VERSION 5.8 ;
BUSBITCHARS "[]" ;
DIVIDERCHAR "/" ;
UNITS
    DATABASE MICRONS 1000 ;
END UNITS

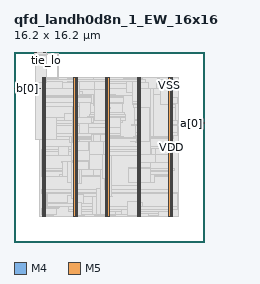
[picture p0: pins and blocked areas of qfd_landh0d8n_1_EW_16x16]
MACRO qfd_landh0d8n_1_EW_16x16
  FOREIGN qfd_landh0d8n_1_EW_16x16 0 0 ;
  CLASS BLOCK ;
  SIZE 16.2 BY 16.2 ;
  PIN a[0]
    DIRECTION INPUT ;
    USE SIGNAL ;
    PORT
      LAYER M4 ;
        RECT  16.116 10.128 16.2 10.152 ;
    END
    PORT
      LAYER M4 ;
        RECT  15.397 10.128 16.14 10.152 ;
    END
  END a[0]
  PIN b[0]
    DIRECTION OUTPUT ;
    USE SIGNAL ;
    PORT
      LAYER M4 ;
        RECT  0 13.104 0.084 13.128 ;
    END
    PORT
      LAYER M4 ;
        RECT  0.06 13.104 2.252 13.128 ;
    END
  END b[0]
  PIN ck
    DIRECTION INPUT ;
    USE SIGNAL ;
    PORT
      LAYER M5 ;
        RECT  1.776 16.116 1.8 16.2 ;
    END
  END ck
  PIN ck_s
    DIRECTION INPUT ;
    USE SIGNAL ;
    PORT
      LAYER M5 ;
        RECT  1.872 16.116 1.896 16.2 ;
    END
  END ck_s
  PIN en
    DIRECTION INPUT ;
    USE SIGNAL ;
    PORT
      LAYER M5 ;
        RECT  1.968 16.116 1.992 16.2 ;
    END
  END en
  PIN fault
    DIRECTION OUTPUT ;
    USE SIGNAL ;
    PORT
      LAYER M5 ;
        RECT  2.064 16.116 2.088 16.2 ;
    END
  END fault
  PIN k0
    DIRECTION INPUT ;
    USE SIGNAL ;
    PORT
      LAYER M5 ;
        RECT  2.16 16.116 2.184 16.2 ;
    END
  END k0
  PIN k1
    DIRECTION INPUT ;
    USE SIGNAL ;
    PORT
      LAYER M5 ;
        RECT  2.256 16.116 2.28 16.2 ;
    END
  END k1
  PIN k2
    DIRECTION INPUT ;
    USE SIGNAL ;
    PORT
      LAYER M5 ;
        RECT  2.352 16.116 2.376 16.2 ;
    END
  END k2
  PIN k3
    DIRECTION INPUT ;
    USE SIGNAL ;
    PORT
      LAYER M5 ;
        RECT  2.448 16.116 2.472 16.2 ;
    END
  END k3
  PIN rs
    DIRECTION INPUT ;
    USE SIGNAL ;
    PORT
      LAYER M5 ;
        RECT  2.544 16.116 2.568 16.2 ;
    END
  END rs
  PIN tie_hi
    DIRECTION OUTPUT ;
    USE SIGNAL ;
    PORT
      LAYER M5 ;
        RECT  2.64 16.116 2.664 16.2 ;
    END
  END tie_hi
  PIN tie_lo
    DIRECTION OUTPUT ;
    USE SIGNAL ;
    PORT
      LAYER M5 ;
        RECT  2.736 16.116 2.76 16.2 ;
    END
  END tie_lo
  PIN VDD
    DIRECTION INOUT ;
    USE POWER ;
    PORT
      LAYER M5 ;
        RECT  13.392 2.151 13.512 14.049 ;
        RECT  10.692 2.151 10.812 14.049 ;
        RECT  7.992 2.151 8.112 14.049 ;
        RECT  5.292 2.151 5.412 14.049 ;
        RECT  2.592 2.151 2.712 14.049 ;
    END
  END VDD
  PIN VSS
    DIRECTION INOUT ;
    USE GROUND ;
    PORT
      LAYER M5 ;
        RECT  13.2 2.137 13.32 14.063 ;
        RECT  10.5 2.137 10.62 14.063 ;
        RECT  7.8 2.137 7.92 14.063 ;
        RECT  5.1 2.137 5.22 14.063 ;
        RECT  2.4 2.137 2.52 14.063 ;
    END
  END VSS
  # OT_OBS_CLOSED layer=M5 d_um=1.536 added=6
  OBS
    LAYER RVTN ;
     RECT  2.16 2.16 14.04 2.295 ;
     RECT  2.16 2.565 14.04 2.835 ;
     RECT  2.16 3.105 14.04 3.375 ;
     RECT  2.16 3.645 14.04 3.915 ;
     RECT  2.16 4.185 14.04 4.455 ;
     RECT  2.16 4.725 14.04 4.995 ;
     RECT  2.16 5.265 14.04 5.535 ;
     RECT  2.16 5.805 14.04 6.075 ;
     RECT  2.16 6.345 14.04 6.615 ;
     RECT  2.16 6.885 14.04 7.155 ;
     RECT  2.16 7.425 14.04 7.695 ;
     RECT  2.16 7.965 14.04 8.235 ;
     RECT  2.16 8.505 14.04 8.775 ;
     RECT  2.16 9.045 14.04 9.315 ;
     RECT  2.16 9.585 14.04 9.855 ;
     RECT  2.16 10.125 14.04 10.395 ;
     RECT  2.16 10.665 14.04 10.935 ;
     RECT  2.16 11.205 14.04 11.475 ;
     RECT  2.16 11.745 14.04 12.015 ;
     RECT  2.16 12.285 14.04 12.555 ;
     RECT  2.16 12.825 14.04 13.095 ;
     RECT  2.16 13.365 14.04 13.635 ;
     RECT  2.16 13.905 14.04 14.04 ;
    LAYER RVTP ;
     RECT  2.16 2.295 14.04 2.565 ;
     RECT  2.16 2.835 14.04 3.105 ;
     RECT  2.16 3.375 14.04 3.645 ;
     RECT  2.16 3.915 14.04 4.185 ;
     RECT  2.16 4.455 14.04 4.725 ;
     RECT  2.16 4.995 14.04 5.265 ;
     RECT  2.16 5.535 14.04 5.805 ;
     RECT  2.16 6.075 14.04 6.345 ;
     RECT  2.16 6.615 14.04 6.885 ;
     RECT  2.16 7.155 14.04 7.425 ;
     RECT  2.16 7.695 14.04 7.965 ;
     RECT  2.16 8.235 14.04 8.505 ;
     RECT  2.16 8.775 14.04 9.045 ;
     RECT  2.16 9.315 14.04 9.585 ;
     RECT  2.16 9.855 14.04 10.125 ;
     RECT  2.16 10.395 14.04 10.665 ;
     RECT  2.16 10.935 14.04 11.205 ;
     RECT  2.16 11.475 14.04 11.745 ;
     RECT  2.16 12.015 14.04 12.285 ;
     RECT  2.16 12.555 14.04 12.825 ;
     RECT  2.16 13.095 14.04 13.365 ;
     RECT  2.16 13.635 14.04 13.905 ;
    LAYER M1 ;
     RECT  2.16 2.151 14.04 14.049 ;
    LAYER M2 ;
     RECT  2.16 2.151 14.04 14.049 ;
     RECT  14.04 10.17 15.431 10.188 ;
    LAYER M3 ;
     RECT  2.415 2.143 2.505 2.191 ;
     RECT  7.815 2.143 7.905 2.191 ;
     RECT  5.115 2.143 5.205 2.227 ;
     RECT  10.515 2.143 10.605 2.227 ;
     RECT  5.115 2.227 5.958 2.263 ;
     RECT  6.948 2.227 6.966 2.263 ;
     RECT  7.776 2.191 7.905 2.263 ;
     RECT  2.415 2.191 2.97 2.299 ;
     RECT  6.948 2.263 8.154 2.299 ;
     RECT  2.415 2.299 3.33 2.335 ;
     RECT  2.34 2.335 3.33 2.371 ;
     RECT  5.115 2.263 6.03 2.371 ;
     RECT  6.876 2.299 8.694 2.371 ;
     RECT  9.864 2.227 10.605 2.371 ;
     RECT  9.684 2.371 10.605 2.413 ;
     RECT  11.448 2.299 12.294 2.413 ;
     RECT  13.215 2.143 13.305 2.413 ;
     RECT  5.115 2.371 8.694 2.641 ;
     RECT  9.684 2.413 12.294 2.641 ;
     RECT  13.215 2.413 13.497 2.641 ;
     RECT  4.644 2.641 13.497 2.767 ;
     RECT  2.34 2.371 3.654 2.839 ;
     RECT  2.34 2.839 3.834 2.861 ;
     RECT  2.415 2.861 3.834 2.911 ;
     RECT  2.415 2.911 3.906 3.001 ;
     RECT  4.644 2.767 13.914 3.001 ;
     RECT  2.415 3.001 13.914 4.123 ;
     RECT  2.34 4.123 13.914 4.253 ;
     RECT  2.34 4.253 13.497 4.451 ;
     RECT  2.415 4.451 13.497 5.552 ;
     RECT  2.34 5.552 13.497 5.971 ;
     RECT  2.34 5.971 13.518 6.115 ;
     RECT  2.34 6.115 13.662 6.269 ;
     RECT  2.34 6.269 13.497 7.349 ;
     RECT  2.34 7.349 3.798 7.691 ;
     RECT  4.608 7.349 13.497 7.735 ;
     RECT  2.376 7.691 3.798 7.889 ;
     RECT  4.608 7.735 13.806 7.889 ;
     RECT  2.415 7.889 3.798 8.167 ;
     RECT  4.608 7.889 13.497 8.167 ;
     RECT  2.415 8.167 13.497 8.851 ;
     RECT  2.415 8.851 13.59 8.879 ;
     RECT  2.415 8.879 9.378 8.969 ;
     RECT  10.224 8.879 13.59 8.969 ;
     RECT  10.368 8.969 13.59 9.085 ;
     RECT  2.415 8.969 9.09 9.239 ;
     RECT  10.368 9.085 13.95 9.311 ;
     RECT  6.336 9.239 9.09 9.779 ;
     RECT  2.415 9.239 5.562 9.931 ;
     RECT  10.368 9.311 13.914 9.931 ;
     RECT  10.008 9.931 13.914 10.049 ;
     RECT  2.376 9.931 5.562 10.085 ;
     RECT  2.415 10.085 5.562 10.123 ;
     RECT  6.336 9.779 8.097 10.123 ;
     RECT  15.408 10.123 15.426 10.193 ;
     RECT  9.072 9.779 9.09 10.201 ;
     RECT  9.072 10.201 9.234 10.327 ;
     RECT  10.26 10.049 13.914 10.391 ;
     RECT  2.415 10.123 8.097 10.633 ;
     RECT  9.072 10.327 9.486 10.633 ;
     RECT  2.415 10.633 9.486 10.637 ;
     RECT  6.3 10.637 9.486 10.661 ;
     RECT  6.408 10.661 9.486 10.859 ;
     RECT  6.48 10.859 9.414 11.039 ;
     RECT  10.26 10.391 13.77 11.479 ;
     RECT  2.415 10.637 5.562 11.515 ;
     RECT  10.224 11.479 13.77 11.749 ;
     RECT  6.48 11.039 9.27 11.821 ;
     RECT  10.116 11.749 13.77 11.821 ;
     RECT  2.34 11.515 5.562 11.911 ;
     RECT  6.48 11.821 9.342 11.911 ;
     RECT  10.116 11.821 13.914 12.353 ;
     RECT  2.34 11.911 9.342 12.361 ;
     RECT  2.304 12.361 9.342 12.413 ;
     RECT  10.116 12.353 13.554 12.479 ;
     RECT  2.34 12.413 9.342 12.523 ;
     RECT  10.116 12.479 13.497 12.523 ;
     RECT  2.34 12.523 13.497 13.127 ;
     RECT  12.168 13.127 13.497 13.405 ;
     RECT  2.34 13.127 11.43 13.559 ;
     RECT  2.34 13.559 11.25 13.595 ;
     RECT  12.168 13.405 13.59 13.595 ;
     RECT  12.24 13.595 13.59 13.639 ;
     RECT  2.34 13.595 11.214 13.829 ;
     RECT  12.24 13.639 13.914 13.829 ;
     RECT  4.572 13.829 5.238 13.865 ;
     RECT  6.12 13.829 7.905 13.865 ;
     RECT  12.276 13.829 13.59 13.865 ;
     RECT  2.34 13.829 3.762 13.901 ;
     RECT  6.768 13.865 6.786 13.901 ;
     RECT  9.36 13.829 10.962 13.901 ;
     RECT  12.276 13.865 12.438 13.901 ;
     RECT  13.176 13.865 13.305 13.901 ;
     RECT  12.276 13.901 12.294 13.937 ;
     RECT  2.34 13.901 2.898 13.945 ;
     RECT  4.572 13.865 5.205 13.973 ;
     RECT  2.304 13.945 2.898 14.009 ;
     RECT  9.36 13.901 10.605 14.009 ;
     RECT  5.115 13.973 5.205 14.057 ;
     RECT  7.815 13.865 7.905 14.057 ;
     RECT  10.515 14.009 10.605 14.057 ;
     RECT  13.215 13.901 13.305 14.057 ;
     RECT  2.304 14.009 2.79 14.059 ;
     RECT  2.268 14.059 2.79 14.189 ;
     RECT  2.304 14.189 2.79 15.389 ;
     RECT  2.304 15.389 2.358 16.013 ;
     RECT  3.744 13.901 3.762 16.061 ;
     RECT  2.304 16.013 2.322 16.109 ;
    LAYER M4 ;
     RECT  1.765 15.936 1.957 15.96 ;
     RECT  2.005 10.368 2.245 10.392 ;
     RECT  2.252 12.384 2.257 13.128 ;
     RECT  1.957 15.936 2.333 16.104 ;
     RECT  2.257 12.384 2.365 14.184 ;
     RECT  2.329 2.832 2.408 2.856 ;
     RECT  2.329 4.128 2.408 4.152 ;
     RECT  2.329 5.568 2.408 5.592 ;
     RECT  1.861 8.736 2.408 8.76 ;
     RECT  2.245 10.368 2.408 11.16 ;
     RECT  2.365 12.384 2.408 14.232 ;
     RECT  2.408 2.148 2.512 14.232 ;
     RECT  2.588 14.832 2.675 14.856 ;
     RECT  2.512 2.418 2.704 13.782 ;
     RECT  2.333 15.936 2.717 16.056 ;
     RECT  2.717 15.36 2.801 16.056 ;
     RECT  2.704 2.832 2.819 4.152 ;
     RECT  2.801 15.984 2.819 16.056 ;
     RECT  2.704 8.736 3.593 10.632 ;
     RECT  2.819 16.032 3.773 16.056 ;
     RECT  2.704 5.568 3.841 5.592 ;
     RECT  3.841 5.568 3.913 5.736 ;
     RECT  2.704 13.056 4.097 13.656 ;
     RECT  3.913 5.568 4.165 5.784 ;
     RECT  4.021 6.816 4.165 6.84 ;
     RECT  3.593 10.368 4.345 10.632 ;
     RECT  2.819 3.312 4.525 3.336 ;
     RECT  4.165 5.568 4.525 6.84 ;
     RECT  3.593 8.736 4.705 9 ;
     RECT  4.525 5.04 4.885 6.84 ;
     RECT  4.885 5.04 4.921 6.936 ;
     RECT  4.705 8.496 4.921 9 ;
     RECT  4.345 10.368 4.949 10.92 ;
     RECT  4.921 5.04 5.065 9 ;
     RECT  4.525 3.312 5.108 3.96 ;
     RECT  5.065 4.992 5.108 9 ;
     RECT  4.949 10.368 5.108 11.544 ;
     RECT  4.525 13.68 5.108 13.704 ;
     RECT  5.108 2.148 5.212 14.052 ;
     RECT  5.212 2.256 5.404 13.782 ;
     RECT  5.404 4.992 5.555 8.76 ;
     RECT  5.404 12.528 5.555 13.704 ;
     RECT  5.555 4.992 5.789 6.936 ;
     RECT  5.555 12.576 5.825 12.792 ;
     RECT  5.404 2.256 5.93 2.328 ;
     RECT  5.404 3.312 5.933 4.008 ;
     RECT  5.825 12.576 6.613 12.6 ;
     RECT  5.555 7.92 6.649 8.76 ;
     RECT  5.404 10.128 6.65 10.632 ;
     RECT  5.93 2.304 6.685 2.328 ;
     RECT  5.933 3.312 6.685 3.864 ;
     RECT  6.613 11.808 6.757 12.6 ;
     RECT  5.789 5.712 6.793 6.936 ;
     RECT  6.649 7.92 6.793 9.144 ;
     RECT  6.65 10.176 6.797 10.632 ;
     RECT  6.797 10.32 6.829 10.632 ;
     RECT  6.757 11.664 6.829 12.6 ;
     RECT  6.829 10.32 6.853 12.6 ;
     RECT  6.685 13.68 6.853 13.704 ;
     RECT  6.685 2.304 7.009 3.864 ;
     RECT  7.009 2.304 7.369 4.536 ;
     RECT  6.793 5.712 7.369 9.144 ;
     RECT  7.369 2.304 7.808 9.144 ;
     RECT  6.853 10.32 7.808 13.704 ;
     RECT  7.808 2.148 7.912 14.052 ;
     RECT  7.912 2.304 8.104 13.782 ;
     RECT  8.104 3.84 8.165 7.752 ;
     RECT  8.104 11.424 8.237 11.448 ;
     RECT  8.165 3.84 8.309 7.368 ;
     RECT  8.309 3.84 8.381 3.864 ;
     RECT  8.104 12.528 8.633 12.552 ;
     RECT  8.104 9.072 9.101 9.096 ;
     RECT  8.104 2.304 9.205 2.328 ;
     RECT  8.104 13.536 9.601 13.704 ;
     RECT  9.205 2.304 9.685 2.808 ;
     RECT  9.601 12.768 10.105 13.704 ;
     RECT  9.961 8.544 10.393 8.568 ;
     RECT  10.393 8.496 10.465 8.568 ;
     RECT  9.685 2.304 10.508 3.432 ;
     RECT  8.309 4.848 10.508 7.368 ;
     RECT  10.465 8.496 10.508 9 ;
     RECT  10.393 10.416 10.508 10.44 ;
     RECT  10.105 12 10.508 13.704 ;
     RECT  10.508 2.148 10.612 14.052 ;
     RECT  10.612 2.418 10.804 13.782 ;
     RECT  10.804 3.024 10.973 3.336 ;
     RECT  10.804 5.04 11.651 13.08 ;
     RECT  11.651 6.72 11.657 13.08 ;
     RECT  11.657 6.816 11.665 13.08 ;
     RECT  11.665 6.816 11.765 7.992 ;
     RECT  11.665 8.976 11.909 13.08 ;
     RECT  11.651 5.04 11.945 5.736 ;
     RECT  11.765 6.816 12.035 7.944 ;
     RECT  10.973 3.024 12.053 3.048 ;
     RECT  11.945 5.712 13.208 5.736 ;
     RECT  12.035 7.056 13.208 7.944 ;
     RECT  11.909 8.976 13.208 12.552 ;
     RECT  12.517 13.68 13.208 13.704 ;
     RECT  13.208 2.148 13.312 14.052 ;
     RECT  13.312 2.418 13.504 13.782 ;
    LAYER M5 ;
     RECT  2.4 2.137 2.52 2.151 ;
     RECT  5.1 2.137 5.22 2.151 ;
     RECT  7.8 2.137 7.92 2.151 ;
     RECT  10.5 2.137 10.62 2.151 ;
     RECT  13.2 2.137 13.32 2.151 ;
     RECT  5.1 2.151 5.412 2.245 ;
     RECT  10.5 2.151 10.812 2.293 ;
     RECT  2.4 2.151 2.712 2.821 ;
     RECT  5.1 2.245 5.736 3.347 ;
     RECT  9.696 2.293 10.812 3.443 ;
     RECT  5.1 3.347 5.412 3.685 ;
     RECT  2.4 2.821 2.808 4.163 ;
     RECT  7.8 2.151 8.112 4.501 ;
     RECT  10.5 3.443 10.812 5.077 ;
     RECT  7.68 4.501 8.112 5.413 ;
     RECT  9.744 5.077 10.812 6.277 ;
     RECT  9.744 6.277 11.64 6.323 ;
     RECT  4.944 3.685 5.412 6.805 ;
     RECT  10.5 6.323 11.64 6.805 ;
     RECT  4.896 6.805 5.412 6.853 ;
     RECT  6.384 6.181 6.408 6.853 ;
     RECT  4.896 6.853 6.408 6.947 ;
     RECT  7.536 5.413 8.112 7.475 ;
     RECT  10.5 6.805 12.024 7.475 ;
     RECT  5.1 6.947 6.408 7.763 ;
     RECT  5.1 7.763 5.412 8.485 ;
     RECT  6.384 7.763 6.408 8.579 ;
     RECT  7.632 7.475 8.112 8.579 ;
     RECT  10.5 7.475 11.64 8.579 ;
     RECT  2.4 4.163 2.712 8.725 ;
     RECT  10.5 8.579 11.592 11.459 ;
     RECT  4.992 8.485 5.412 11.555 ;
     RECT  13.2 2.151 13.512 11.749 ;
     RECT  5.1 11.555 5.412 12.517 ;
     RECT  7.8 8.579 8.112 13.045 ;
     RECT  1.872 8.725 2.712 13.621 ;
     RECT  5.1 12.517 5.544 13.715 ;
     RECT  6.864 13.045 8.112 13.715 ;
     RECT  12.528 11.749 13.512 13.715 ;
     RECT  5.1 13.715 5.412 14.049 ;
     RECT  7.8 13.715 8.112 14.049 ;
     RECT  10.5 11.459 10.812 14.049 ;
     RECT  13.2 13.715 13.512 14.049 ;
     RECT  5.1 14.049 5.22 14.063 ;
     RECT  7.8 14.049 7.92 14.063 ;
     RECT  10.5 14.049 10.62 14.063 ;
     RECT  13.2 14.049 13.32 14.063 ;
     RECT  1.872 13.621 2.808 15.925 ;
     RECT  1.776 15.925 2.808 16.019 ;
     RECT  1.776 16.019 2.76 16.116 ;
     RECT  1.8 16.116 1.872 16.144 ;
     RECT  1.896 16.116 1.968 16.144 ;
     RECT  1.992 16.116 2.064 16.144 ;
     RECT  2.088 16.116 2.16 16.144 ;
     RECT  2.184 16.116 2.256 16.144 ;
     RECT  2.28 16.116 2.352 16.144 ;
     RECT  2.376 16.116 2.448 16.144 ;
     RECT  2.472 16.116 2.544 16.144 ;
     RECT  2.568 16.116 2.64 16.144 ;
     RECT  2.664 16.116 2.736 16.144 ;
     RECT  5.412 6.181 6.384 6.853 ;
     RECT  6.408 6.181 7.536 7.475 ;
     RECT  12.024 6.805 13.2 7.475 ;
     RECT  6.408 7.475 7.632 8.579 ;
     RECT  5.412 7.763 6.384 8.579 ;
     RECT  5.544 13.045 6.864 13.715 ;
  END
END qfd_landh0d8n_1_EW_16x16
END LIBRARY
